VERSION 5.8 ;
BUSBITCHARS "[]" ;
DIVIDERCHAR "/" ;

UNITS
  DATABASE MICRONS 1000 ;
END UNITS

MANUFACTURINGGRID 0.005 ;

PROPERTYDEFINITIONS
  LAYER LEF58_BACKSIDE STRING ;
END PROPERTYDEFINITIONS

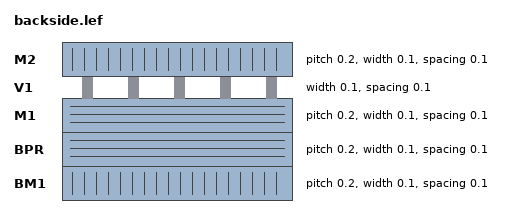
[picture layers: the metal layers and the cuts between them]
LAYER BM1
  TYPE ROUTING ;
  DIRECTION VERTICAL ;
  PITCH 0.2 ;
  WIDTH 0.1 ;
  SPACING 0.1 ;
  PROPERTY LEF58_BACKSIDE "BACKSIDE ;" ;
END BM1

LAYER BPR
  TYPE ROUTING ;
  DIRECTION HORIZONTAL ;
  PITCH 0.2 ;
  WIDTH 0.1 ;
  SPACING 0.1 ;
  PROPERTY LEF58_BACKSIDE "BACKSIDE ;" ;
END BPR

LAYER M1
  TYPE ROUTING ;
  DIRECTION HORIZONTAL ;
  PITCH 0.2 ;
  WIDTH 0.1 ;
  SPACING 0.1 ;
END M1

LAYER V1
  TYPE CUT ;
  WIDTH 0.1 ;
  SPACING 0.1 ;
END V1

LAYER M2
  TYPE ROUTING ;
  DIRECTION VERTICAL ;
  PITCH 0.2 ;
  WIDTH 0.1 ;
  SPACING 0.1 ;
END M2

END LIBRARY
